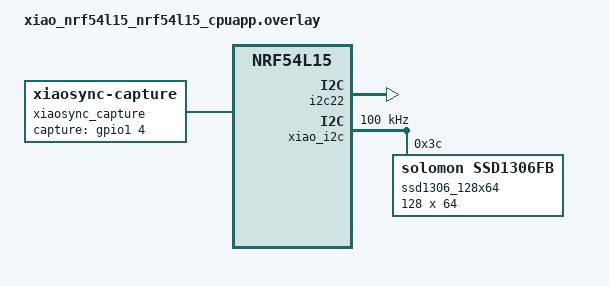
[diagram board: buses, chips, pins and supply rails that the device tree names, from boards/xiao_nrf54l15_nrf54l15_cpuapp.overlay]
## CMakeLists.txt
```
# Copyright (c) 2026 Semtech Corporation
# SPDX-License-Identifier: Apache-2.0

cmake_minimum_required(VERSION 3.13.1)

list(APPEND ZEPHYR_EXTRA_MODULES ${CMAKE_CURRENT_SOURCE_DIR}/usp_preview/usp_zephyr)
list(APPEND ZEPHYR_EXTRA_MODULES ${CMAKE_CURRENT_SOURCE_DIR}/usp_preview/usp)

set(SHIELD semtech_wio_lr2021)

find_package(Zephyr REQUIRED HINTS $ENV{ZEPHYR_BASE})
project(swdm031_img_xfer)

# Add the application files
if(CONFIG_TRANSMITTER)
file(GLOB IMAGE_DEMO_SRC src/transmitter/*.c)
target_include_directories(app PRIVATE src/transmitter )
elseif(CONFIG_RECEIVER)
file(GLOB IMAGE_DEMO_SRC src/receiver/*.c)
target_include_directories(app PRIVATE src/receiver )
endif()

target_include_directories(app PRIVATE
    src/common
    src/xiaosync
)
file(GLOB COMMON src/common/*.c)

target_sources(app PRIVATE
    ${COMMON}
    ${IMAGE_DEMO_SRC}
    src/main.c
    src/xiaosync/xiaosync.c
)
```

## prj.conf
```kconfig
# Copyright (c) 2024 Semtech Corporation
# SPDX-License-Identifier: Apache-2.0

# --------------------------- General configuration ---------------------------

CONFIG_SPEED_OPTIMIZATIONS=y          # -O2 ou -O3
CONFIG_SIZE_OPTIMIZATIONS=n           # Vitesse > taille

CONFIG_ICACHE=y

CONFIG_USE_SEGGER_RTT=n
# heap size
CONFIG_HEAP_MEM_POOL_SIZE=20480
CONFIG_LOG=y
CONFIG_LOG_BUFFER_SIZE=4096

CONFIG_TEST_RANDOM_GENERATOR=y
CONFIG_PM_DEVICE=y
CONFIG_WATCHDOG=n
CONFIG_FLASH=y

# ------------------------------ Transceiver driver ----------------------------

CONFIG_LORA_BASICS_MODEM_DRIVERS=y
CONFIG_LORA_BASICS_MODEM_DRIVERS_EVENT_TRIGGER_GLOBAL_THREAD=n
CONFIG_LORA_BASICS_MODEM_DRIVERS_EVENT_TRIGGER_NO_THREAD=y

# ------------------------------ USP -----------------------------

CONFIG_USP=y
CONFIG_USP_MAIN_THREAD=y

#CONFIG_USP_LOG_LEVEL_DBG=y
#CONFIG_USP_LOG_VERBOSE=n

# no picolibc (Windows issue)
CONFIG_PICOLIBC_USE_MODULE=n
CONFIG_NEWLIB_LIBC=y

CONFIG_MAIN_STACK_SIZE=4096
CONFIG_STACK_SENTINEL=y

# Debug stack (à enlever en production)
CONFIG_THREAD_STACK_INFO=y
CONFIG_STACK_SENTINEL=y
CONFIG_THREAD_MONITOR=y
CONFIG_THREAD_NAME=y

# Threads are cooperative (non-preemptive) to simplify critical section management and avoid complex synchronization.
# This approach may reduce reactivity when ISR (interrupt service routines) are triggered (low optimization)
# The USP RAC thread is assigned a higher priority: it will execute immediately once the Main thread yields or blocks, ensuring prompt handling of USP RAC-related tasks.
# The Main thread has a lower priority: it runs only when the USP RAC thread is idle or waiting
CONFIG_MAIN_THREAD_PRIORITY=-2
CONFIG_USP_MAIN_THREAD_PRIORITY=-4

# Threads are preemptive: a thread with a higher priority can interrupt (preempt) a lower priority thread at any time.
# USP RAC thread has higher priority (1): it will preempt the main thread immediately whenever it is ready to run (ISR/Timer), ensuring low latency and fast response for USP RAC-related tasks.
# Main thread has lower priority (3): it runs only when the USP RAC thread is not active, yielding CPU time to the more urgent USP RAC operations automatically.
# This priority scheme allows responsive multitasking with guaranteed preemption based on thread priority.
# CONFIG_MAIN_THREAD_PRIORITY=3
# CONFIG_USP_MAIN_THREAD_PRIORITY=1
# CONFIG_USP_THREADS_MUTEXES=y

#
# Priority Inversion : In case of multiple threads with different priorities, consider the modification of existing priorities and mutex use, or use Zephyr capabilities :
# CONFIG_KERNEL_MEM_POOL=y
# CONFIG_MUTEX_PRIORITY_INHERITANCE=y
# CONFIG_PRIORITY_CEILING=y

# Only one thread
# CONFIG_USP_MAIN_THREAD_PRIORITY=0

# Stack trace automatique
CONFIG_DEBUG_THREAD_INFO=y
CONFIG_DEBUG_OPTIMIZATIONS=y

# Meilleure trace des exceptions
CONFIG_EXTRA_EXCEPTION_INFO=y
CONFIG_FAULT_DUMP=2

CONFIG_SSD1306=y
CONFIG_DISPLAY=y
CONFIG_CHARACTER_FRAMEBUFFER=y
CONFIG_DISPLAY_LOG_LEVEL_ERR=y

CONFIG_LVGL=y
CONFIG_LV_Z_MEM_POOL_SIZE=8192
CONFIG_LV_Z_VDB_SIZE=64
CONFIG_LV_DPI_DEF=148
CONFIG_LV_Z_BITS_PER_PIXEL=1
CONFIG_LV_COLOR_DEPTH_1=y

CONFIG_LV_USE_LOG=y
CONFIG_LV_USE_LABEL=y
CONFIG_LV_USE_ARC=y
CONFIG_LV_USE_MONKEY=y
CONFIG_LV_USE_IMAGE=y

# It might cause an error if the "CONFIG_LV_USE_THEME_DEFAULT=y" is set when using Zephyr > V4.0
CONFIG_LV_USE_THEME_SIMPLE=y
CONFIG_LV_USE_THEME_MONO=n

# CONFIG_RECEIVER=y

# ------------------------------ TIME SYNC & UART ------------------------------
# Abilita le API avanzate per la porta seriale
CONFIG_SERIAL=y

# Abilita la ricezione asincrona via interrupt (fondamentale per non bloccare la radio)
CONFIG_UART_INTERRUPT_DRIVEN=y

# Abilita le API per l'orologio di sistema (Real Time Clock)
CONFIG_RTC=y
CONFIG_COUNTER=y

# Abilita il driver hardware per la sincronizzazione (DPPI)
CONFIG_NRFX_GPPI=y

CONFIG_GPIO=y
# Abilita il driver hardware per la sincronizzazione (DPPI)
CONFIG_NRFX_GRTC=y
```

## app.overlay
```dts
/*
 * Edge-detector for the external trigger signal
 * https://files.seeedstudio.com/wiki/XIAO_nRF54L15/Getting_Start/nr_definition.png
 */

/ {
  xiaosync_capture: xiaosync-capture {
    compatible = "zephyr,xiaosync-capture";
    capture-gpios = <&gpio1 4 (GPIO_PULL_DOWN | GPIO_ACTIVE_HIGH)>;
    capture-edge = <0>;
  };

  aliases {
    sync0 = &xiaosync_capture;
  };
};
```

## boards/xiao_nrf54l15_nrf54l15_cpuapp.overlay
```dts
// /*
//  * Copyright (c) 2024 Semtech Corporation
//  *
//  * SPDX-License-Identifier: Apache-2.0
//  */

/ {
	aliases {
		smtc-watchdog = &wdt31;
		smtc-user-button = &usr_btn;
	};
	chosen {
		zephyr,display = &ssd1306_128x64;
	};
};

&xiao_serial {
	status = "disabled";
};

&i2c22 {
	status = "okay";
};

&i2c30 {
	status = "disabled";
};

&adc {
	status = "disabled";
};

&wdt31 {
	status = "disabled";
};

&xiao_i2c {
	status = "okay";
    clock-frequency = <I2C_BITRATE_STANDARD>;
	zephyr,concat-buf-size = <4096>;

    ssd1306_128x64: ssd1306@3c {
		compatible = "solomon,ssd1306fb";
		reg = <0x3c>;
		width = <128>;
		height = <64>;
		segment-offset = <0>;
		page-offset = <0>;
		display-offset = <0>;
		multiplex-ratio = <63>;
		segment-remap;
		com-invdir;
		
		prechargep = <0x22>;
		inversion-on;
	};
};

/* --- AGGIUNTA PER LA SINCRONIZZAZIONE --- */
/ {
  xiaosync_capture: xiaosync-capture {
    compatible = "zephyr,xiaosync-capture";
    /* gpio1 4 corrisponde fisicamente al PIN D0 sulla XIAO! */
    capture-gpios = <&gpio1 4 (GPIO_PULL_DOWN | GPIO_ACTIVE_HIGH)>;
    capture-edge = <0>;
  };

  aliases {
    sync0 = &xiaosync_capture;
  };
};
```

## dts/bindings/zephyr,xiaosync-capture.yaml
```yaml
description: Edge detector device

compatible: "zephyr,xiaosync-capture"

include: base.yaml

properties:
  capture-gpios:
    type: phandle-array
    required: true
    description: GPIO pin for the external trigger signal.

  capture-edge:
    type: int
    required: true
    description: Trigger signal active edge (0 = rising; 1 = falling; 2 = either)
```

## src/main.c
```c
/**
 * @file      main.c
 *
 * @brief     Application main
 *
 * The Clear BSD License
 * Copyright Semtech Corporation 2026. All rights reserved.
 *
 * Redistribution and use in source and binary forms, with or without
 * modification, are permitted (subject to the limitations in the disclaimer
 * below) provided that the following conditions are met:
 *     * Redistributions of source code must retain the above copyright
 *       notice, this list of conditions and the following disclaimer.
 *     * Redistributions in binary form must reproduce the above copyright
 *       notice, this list of conditions and the following disclaimer in the
 *       documentation and/or other materials provided with the distribution.
 *     * Neither the name of the Semtech corporation nor the
 *       names of its contributors may be used to endorse or promote products
 *       derived from this software without specific prior written permission.
 *
 * NO EXPRESS OR IMPLIED LICENSES TO ANY PARTY'S PATENT RIGHTS ARE GRANTED BY
 * THIS LICENSE. THIS SOFTWARE IS PROVIDED BY THE COPYRIGHT HOLDERS AND
 * CONTRIBUTORS "AS IS" AND ANY EXPRESS OR IMPLIED WARRANTIES, INCLUDING, BUT
 * NOT LIMITED TO, THE IMPLIED WARRANTIES OF MERCHANTABILITY AND FITNESS FOR A
 * PARTICULAR PURPOSE ARE DISCLAIMED. IN NO EVENT SHALL SEMTECH CORPORATION BE
 * LIABLE FOR ANY DIRECT, INDIRECT, INCIDENTAL, SPECIAL, EXEMPLARY, OR
 * CONSEQUENTIAL DAMAGES (INCLUDING, BUT NOT LIMITED TO, PROCUREMENT OF
 * SUBSTITUTE GOODS OR SERVICES; LOSS OF USE, DATA, OR PROFITS; OR BUSINESS
 * INTERRUPTION) HOWEVER CAUSED AND ON ANY THEORY OF LIABILITY, WHETHER IN
 * CONTRACT, STRICT LIABILITY, OR TORT (INCLUDING NEGLIGENCE OR OTHERWISE)
 * ARISING IN ANY WAY OUT OF THE USE OF THIS SOFTWARE, EVEN IF ADVISED OF THE
 * POSSIBILITY OF SUCH DAMAGE.
 */

#include <stdint.h>   // C99 types
#include <stdbool.h>  // bool type

#include <lvgl.h>
#include <zephyr/device.h>
#include <zephyr/kernel.h>
#include <zephyr/drivers/gpio.h>
#include <zephyr/drivers/display.h>
#include <zephyr/logging/log.h>
#include <zephyr/devicetree.h>

#include <smtc_modem_hal.h>
#include <smtc_zephyr_usp_api.h>
#include <smtc_sw_platform_helper.h>
#include "apps_configuration.h"
#include "lr20xx_system.h"
#include "../xiaosync/xiaosync.h"

#if CONFIG_TRANSMITTER
#include "flrc_burst_tx.h"
#endif

/*
 * -----------------------------------------------------------------------------
 * --- PRIVATE MACROS-----------------------------------------------------------
 */

LOG_MODULE_REGISTER( img_xfer, LOG_LEVEL_INF );

/**
 * @brief Led on the XIAO board.
 */
#define LED0_NODE DT_ALIAS( led0 )
#if !DT_NODE_HAS_STATUS( LED0_NODE, okay )
#error "Unsupported board: led0 devicetree alias is not defined"
#endif

/**
 * @brief User button on the XIAO board.
 */
#define USER_BUTTON_NODE DT_ALIAS( smtc_user_button )
#if !DT_NODE_HAS_STATUS( USER_BUTTON_NODE, okay )
#error "Unsupported board: smtc-user-button devicetree alias is not defined"
#endif

/*
 * -----------------------------------------------------------------------------
 * --- PRIVATE CONSTANTS -------------------------------------------------------
 */

static const struct gpio_dt_spec usr_led = GPIO_DT_SPEC_GET( LED0_NODE, gpios );
static const struct gpio_dt_spec button  = GPIO_DT_SPEC_GET_OR( USER_BUTTON_NODE, gpios, { 0 } );

/*
 * -----------------------------------------------------------------------------
 * --- PRIVATE TYPES -----------------------------------------------------------
 */

static struct gpio_callback button_cb_data;
static volatile bool        user_button_is_press = false;  // Flag for button status

/*
 * -----------------------------------------------------------------------------
 * --- PRIVATE VARIABLES -------------------------------------------------------
 */

/**
 * @brief Startup animation
 */
static uint8_t anim_completed_count = 0;
static bool    anim_end_flag        = false;

K_SEM_DEFINE( periodical_event_sem, 0, 1 );
/*
 * -----------------------------------------------------------------------------
 * --- PRIVATE FUNCTIONS DECLARATION -------------------------------------------
 */

static void boot_animation( void );
static void animation_completed_cb( lv_anim_t* anim );

static int  configure_user_button( void );
static void user_button_callback( const struct device* dev, struct gpio_callback* cb, uint32_t pins );

/*
 * -----------------------------------------------------------------------------
 * --- PUBLIC FUNCTIONS DEFINITION ---------------------------------------------
 */

int main( void )
{
    LOG_INF("=== BOOT SEQUENCE START ===");
    
    // 1. BOOT ANIMATION
    boot_animation( );
    while( 1 ) {
        lv_timer_handler( );
        if( anim_end_flag == true ) {
            lv_obj_clean( lv_scr_act( ) );
            break;
        }
        k_msleep( 20 );
    }
    k_msleep( 2000 );

    // 2. GPIO SETUP
    if( !gpio_is_ready_dt( &usr_led ) ) {
        LOG_ERR( "user led is not ready" );
    } else {
        gpio_pin_configure_dt( &usr_led, GPIO_OUTPUT_ACTIVE );
    }

    if( configure_user_button( ) != 0 ) {
        LOG_ERR( "Issue when configuring user button, aborting" );
    }

    // 3. SYNC INIT E WAIT PRIMO
    int err = syncInit();
    if (err == 0) {
        syncEnable();  
        printk("Sistema di Sincronizzazione HW pronto su D0\n");
    }

    LOG_INF("Waiting for HW sync edge on P1.04...");
    while (getDeltaMicroSeconds() == -1) {
        k_sleep(K_MSEC(10)); 
    }

    // 4. DISABILITA XIAOSYNC SUBITO DOPO SYNC
    syncDisableComplete(); 
    int64_t delta_us = getDeltaMicroSeconds();
    LOG_INF("✓ Sync detected! Epoch offset: %" PRId64 " us", delta_us);
    
    k_msleep(500);

    // 5. SMTC INIT DOPO CHE XIAOSYNC È DISABILITATO
    SMTC_SW_PLATFORM_INIT( );
    SMTC_SW_PLATFORM_VOID( smtc_rac_init( ) );

    lr20xx_system_version_t version;
    lr20xx_status_t status;
    void* radio_driver_context = smtc_rac_get_radio_driver_context( );
    status = lr20xx_system_get_version( radio_driver_context, &version );
    if( status == LR20XX_STATUS_OK ) {
        LOG_INF( "Major firmware version: 0x%02X", version.major );
        LOG_INF( "Minor firmware version: 0x%02X", version.minor );
    }

    LOG_INF( "===== LR20xx Image Transfer Demo =====" );

    k_msleep(50);

    LOG_INF("✓ Starting image transfer\n");
    image_transfer_entry( );

    // Main loop
    while( true ) {
        if( user_button_is_press == true ) {
            user_button_is_press = false;
#if CONFIG_TRANSMITTER
            flrc_raw_bit_rate_changed( );
#endif
            LOG_INF( "User button pushed" );
        }
        if( user_button_is_press == false ) {
            k_sem_take( &periodical_event_sem, K_MSEC( 1000 ) );
        }
        gpio_pin_toggle_dt( &usr_led );
    }
    return 0;
}
/*
 * -----------------------------------------------------------------------------
 * --- PRIVATE FUNCTIONS DEFINITION --------------------------------------------
 */
static void animation_completed_cb( lv_anim_t* anim )
{
    anim_completed_count++;
    if( anim_completed_count >= 2 )  // Both width and height animations completed
    {
        anim_end_flag = true;
    }
}

static void boot_animation( void )
{
    // Reset animation completion counter
    anim_completed_count = 0;
    anim_end_flag        = false;

    LV_IMG_DECLARE( lora_logo );
    lv_obj_t* img = lv_img_create( lv_scr_act( ) );
    lv_img_set_src( img, &lora_logo );
    lv_obj_align( img, LV_ALIGN_CENTER, 0, 0 );

    // Set the initial size - 10%
    uint16_t target_w = lora_logo.header.w;
    uint16_t target_h = lora_logo.header.h;
    lv_obj_set_size( img, target_w * 0.1, target_h * 0.1 );

    // Define the animation - width and height
    lv_anim_t anim_w, anim_h;
    // width
    lv_anim_init( &anim_w );
    lv_anim_set_var( &anim_w, img );
    lv_anim_set_exec_cb( &anim_w, ( lv_anim_exec_xcb_t ) lv_obj_set_width );
    lv_anim_set_time( &anim_w, 1000 );                        // animation duration 1s
    lv_anim_set_values( &anim_w, target_w * 0.1, target_w );  // from 10% to 100%
    lv_anim_set_ready_cb( &anim_w, animation_completed_cb );  // End callback
    // height
    lv_anim_init( &anim_h );
    lv_anim_set_var( &anim_h, img );
    lv_anim_set_exec_cb( &anim_h, ( lv_anim_exec_xcb_t ) lv_obj_set_height );
    lv_anim_set_time( &anim_h, 1000 );                        // animation duration 1s
    lv_anim_set_values( &anim_h, target_h * 0.1, target_h );  // from 10% to 100%
    lv_anim_set_ready_cb( &anim_h, animation_completed_cb );  // End callback
    lv_anim_start( &anim_w );
    lv_anim_start( &anim_h );
}

static void user_button_callback( const struct device* dev, struct gpio_callback* cb, uint32_t pins )
{
    static uint32_t last_press_timestamp_ms = 0;

    // Debounce the button press, avoid multiple triggers
    if( ( int32_t ) ( smtc_modem_hal_get_time_in_ms( ) - last_press_timestamp_ms ) > 500 )
    {
        last_press_timestamp_ms = smtc_modem_hal_get_time_in_ms( );
        user_button_is_press    = true;
    }
    // Wake up the main thread
    k_sem_give( &periodical_event_sem );
}

static int configure_user_button( void )
{
    int ret = 0;
    if( !gpio_is_ready_dt( &button ) )
    {
        printk( "Error: button device %s is not ready\n", button.port->name );
        return 1;
    }

    ret = gpio_pin_configure_dt( &button, GPIO_INPUT );
    if( ret != 0 )
    {
        printk( "Error %d: failed to configure %s pin %d\n", ret, button.port->name, button.pin );
        return 1;
    }

    ret = gpio_pin_interrupt_configure_dt( &button, GPIO_INT_EDGE_TO_ACTIVE );
    if( ret != 0 )
    {
        printk( "Error %d: failed to configure interrupt on %s pin %d\n", ret, button.port->name, button.pin );
        return 1;
    }

    gpio_init_callback( &button_cb_data, user_button_callback, BIT( button.pin ) );
    gpio_add_callback( button.port, &button_cb_data );

    return 0;
}

/* --- EOF ------------------------------------------------------------------ */
```
